VERSION 5.7 ;
  NOWIREEXTENSIONATPIN ON ;
  DIVIDERCHAR "/" ;
  BUSBITCHARS "[]" ;
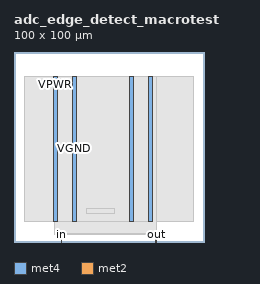
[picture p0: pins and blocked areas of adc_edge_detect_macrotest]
MACRO adc_edge_detect_macrotest
  CLASS BLOCK ;
  FOREIGN adc_edge_detect_macrotest ;
  ORIGIN 0.000 0.000 ;
  SIZE 100.000 BY 100.000 ;
  PIN VGND
    DIRECTION INOUT ;
    USE GROUND ;
    PORT
      LAYER met4 ;
        RECT 31.040 10.640 32.640 87.280 ;
    END
    PORT
      LAYER met4 ;
        RECT 71.040 10.640 72.640 87.280 ;
    END
  END VGND
  PIN VPWR
    DIRECTION INOUT ;
    USE POWER ;
    PORT
      LAYER met4 ;
        RECT 21.040 10.640 22.640 87.280 ;
    END
    PORT
      LAYER met4 ;
        RECT 61.040 10.640 62.640 87.280 ;
    END
  END VPWR
  PIN in
    DIRECTION INPUT ;
    USE SIGNAL ;
    PORT
      LAYER met2 ;
        RECT 24.930 0.000 25.210 4.000 ;
    END
  END in
  PIN out
    DIRECTION OUTPUT TRISTATE ;
    USE SIGNAL ;
    PORT
      LAYER met2 ;
        RECT 74.610 0.000 74.890 4.000 ;
    END
  END out
  OBS
      LAYER nwell ;
        RECT 5.330 82.905 94.490 85.735 ;
        RECT 5.330 77.465 94.490 80.295 ;
        RECT 5.330 72.025 94.490 74.855 ;
        RECT 5.330 66.585 94.490 69.415 ;
        RECT 5.330 61.145 94.490 63.975 ;
        RECT 5.330 55.705 94.490 58.535 ;
        RECT 5.330 50.265 94.490 53.095 ;
        RECT 5.330 44.825 94.490 47.655 ;
        RECT 5.330 39.385 94.490 42.215 ;
        RECT 5.330 33.945 94.490 36.775 ;
        RECT 5.330 28.505 94.490 31.335 ;
        RECT 5.330 23.065 94.490 25.895 ;
        RECT 5.330 17.625 94.490 20.455 ;
        RECT 5.330 12.185 94.490 15.015 ;
      LAYER li1 ;
        RECT 5.520 10.795 94.300 87.125 ;
      LAYER met1 ;
        RECT 5.520 10.640 94.300 87.280 ;
      LAYER met2 ;
        RECT 21.070 4.280 74.880 87.225 ;
        RECT 21.070 4.000 24.650 4.280 ;
        RECT 25.490 4.000 74.330 4.280 ;
      LAYER met3 ;
        RECT 21.050 10.715 72.630 87.205 ;
      LAYER met4 ;
        RECT 37.910 14.890 53.150 17.750 ;
  END
END adc_edge_detect_macrotest
END LIBRARY

